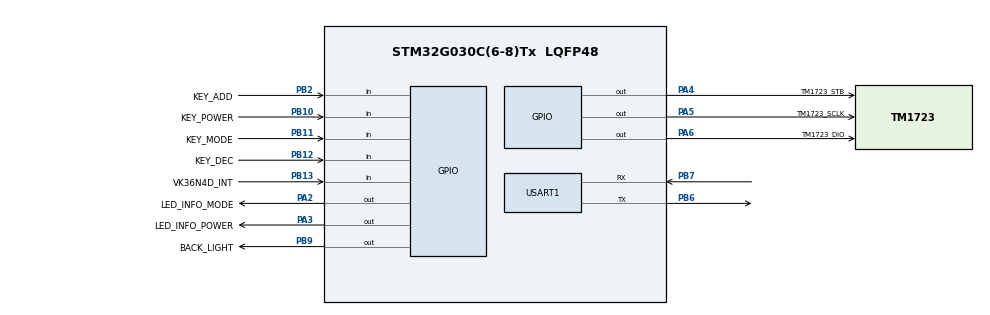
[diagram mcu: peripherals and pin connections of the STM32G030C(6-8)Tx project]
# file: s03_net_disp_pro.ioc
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FREERTOS.Tasks01=defaultTask,0,128,StartDefaultTask,Default,NULL,Dynamic,NULL,NULL
Mcu.Family=STM32G0
Mcu.Name=STM32G030C(6-8)Tx
Mcu.Package=LQFP48
NVIC.TIM17_IRQn=true\:3\:0\:false\:false\:true\:true\:true\:true\:true
NVIC.USART1_IRQn=true\:3\:0\:false\:false\:true\:true\:true\:true\:true
PA2.GPIO_Label=LED_INFO_MODE
PA2.Signal=GPIO_Output
PA3.GPIO_Label=LED_INFO_POWER
PA3.Signal=GPIO_Output
PA4.GPIO_Label=TM1723_STB
PA4.Signal=GPIO_Output
PA5.GPIO_Label=TM1723_SCLK
PA5.Signal=GPIO_Output
PA6.GPIO_Label=TM1723_DIO
PA6.Signal=GPIO_Output
PB10.GPIO_Label=KEY_POWER
PB10.Signal=GPIO_Input
PB11.GPIO_Label=KEY_MODE
PB11.Signal=GPIO_Input
PB12.GPIO_Label=KEY_DEC
PB12.Signal=GPIO_Input
PB13.GPIO_Label=VK36N4D_INT
PB13.Signal=GPIO_Input
PB2.GPIO_Label=KEY_ADD
PB2.Signal=GPIO_Input
PB6.Mode=Asynchronous
PB6.Signal=USART1_TX
PB7.Mode=Asynchronous
PB7.Signal=USART1_RX
PB9.GPIO_Label=BACK_LIGHT
PB9.Signal=GPIO_Output
ProjectManager.HeapSize=0x200
ProjectManager.StackSize=0x400
ProjectManager.TargetToolchain=MDK-ARM V5.32
RCC.ADCFreq_Value=64000000
RCC.AHBFreq_Value=64000000
RCC.CortexFreq_Value=64000000
RCC.EXTERNAL_CLOCK_VALUE=12288000
RCC.HCLKFreq_Value=64000000
RCC.HSE_VALUE=8000000
RCC.HSI_VALUE=16000000
RCC.LSE_VALUE=32768
RCC.SYSCLKFreq_VALUE=64000000
RCC.SYSCLKSource=RCC_SYSCLKSOURCE_PLLCLK
RCC.VCOOutputFreq_Value=128000000
USART1.VirtualMode-Asynchronous=VM_ASYNC
VP_FREERTOS_VS_CMSIS_V1.Mode=CMSIS_V1
VP_TIM17_VS_ClockSourceINT.Mode=Enable_Timer
board=custom

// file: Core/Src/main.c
/* USER CODE BEGIN Header */
/**
  ******************************************************************************
  * @file           : main.c
  * @brief          : Main program body
  ******************************************************************************
  * @attention
  *
  * S04W03 display board for mass version :1.0  DATA:2024.11.16
  *                2.0 DATA.2025.02.19 for mass
  *       modidfy data:2025-04-16,edit version:2.1
  *       modidfy optimize power key of function .DATA.2025.05.10
  *
  *
  *
  ******************************************************************************
  */
/* USER CODE END Header */
#include "main.h"
#include "cmsis_os.h"
#include "tim.h"
#include "usart.h"
#include "gpio.h"

/* USER CODE BEGIN Includes */
#include "bsp.h"
/* USER CODE END Includes */

void SystemClock_Config(void);
void MX_FREERTOS_Init(void);

int main(void)
{

  /* MCU Configuration--------------------------------------------------------*/

  /* Reset of all peripherals, Initializes the Flash interface and the Systick. */
  HAL_Init();

  /* Configure the system clock */
  SystemClock_Config();

  /* Initialize all configured peripherals */
  MX_GPIO_Init();
  MX_TIM17_Init();
  MX_USART1_UART_Init();
  /* USER CODE BEGIN 2 */
  bsp_init();
  HAL_TIM_Base_Start_IT(&htim17);
  UART_Start_Receive_IT(&huart1,inputBuf,1);
  freeRTOS_Handler();

  /* USER CODE END 2 */

  /* Call init function for freertos objects (in cmsis_os2.c) */
 // MX_FREERTOS_Init();

  /* Start scheduler */
 // osKernelStart();

  /* We should never get here as control is now taken by the scheduler */

  /* Infinite loop */
  while (1)
  {

  }
}

void SystemClock_Config(void)
{
  RCC_OscInitTypeDef RCC_OscInitStruct = {0};
  RCC_ClkInitTypeDef RCC_ClkInitStruct = {0};

  /** Configure the main internal regulator output voltage
  */
  HAL_PWREx_ControlVoltageScaling(PWR_REGULATOR_VOLTAGE_SCALE1);

  /** Initializes the RCC Oscillators according to the specified parameters
  * in the RCC_OscInitTypeDef structure.
  */
  RCC_OscInitStruct.OscillatorType = RCC_OSCILLATORTYPE_HSI;
  RCC_OscInitStruct.HSIState = RCC_HSI_ON;
  RCC_OscInitStruct.HSIDiv = RCC_HSI_DIV1;
  RCC_OscInitStruct.HSICalibrationValue = RCC_HSICALIBRATION_DEFAULT;
  RCC_OscInitStruct.PLL.PLLState = RCC_PLL_ON;
  RCC_OscInitStruct.PLL.PLLSource = RCC_PLLSOURCE_HSI;
  RCC_OscInitStruct.PLL.PLLM = RCC_PLLM_DIV1;
  RCC_OscInitStruct.PLL.PLLN = 9;
  RCC_OscInitStruct.PLL.PLLP = RCC_PLLP_DIV2;
  RCC_OscInitStruct.PLL.PLLR = RCC_PLLR_DIV6;
  if (HAL_RCC_OscConfig(&RCC_OscInitStruct) != HAL_OK)
  {
    Error_Handler();
  }

  /** Initializes the CPU, AHB and APB buses clocks
  */
  RCC_ClkInitStruct.ClockType = RCC_CLOCKTYPE_HCLK|RCC_CLOCKTYPE_SYSCLK
                              |RCC_CLOCKTYPE_PCLK1;
  RCC_ClkInitStruct.SYSCLKSource = RCC_SYSCLKSOURCE_PLLCLK;
  RCC_ClkInitStruct.AHBCLKDivider = RCC_SYSCLK_DIV1;
  RCC_ClkInitStruct.APB1CLKDivider = RCC_HCLK_DIV1;

  if (HAL_RCC_ClockConfig(&RCC_ClkInitStruct, FLASH_LATENCY_0) != HAL_OK)
  {
    Error_Handler();
  }
}

void Error_Handler(void)
{
  __disable_irq();
  while (1)
  {
  }
}
